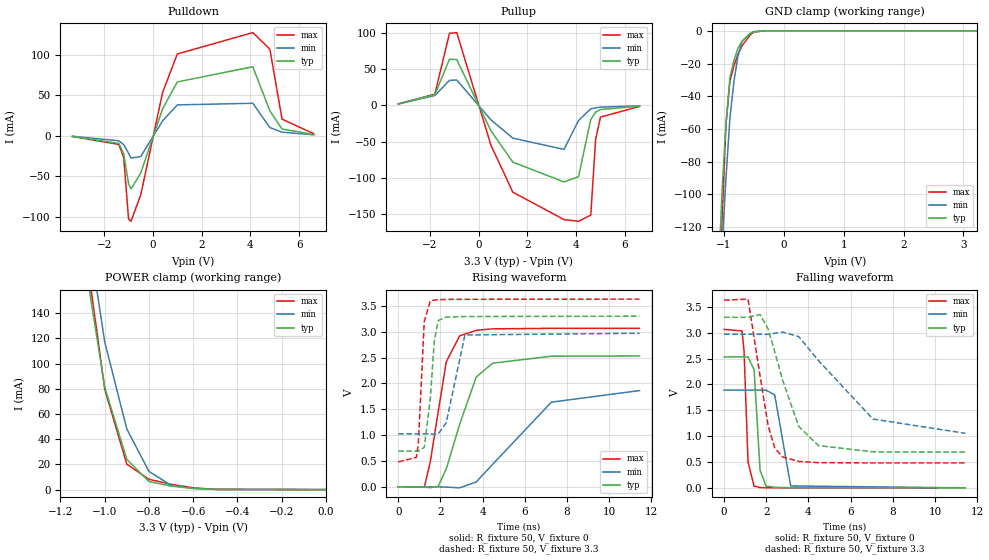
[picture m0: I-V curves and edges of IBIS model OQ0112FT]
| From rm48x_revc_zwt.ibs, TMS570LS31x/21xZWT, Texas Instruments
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|   Model Cell OQ0112FT
|OQ0112FT
[Model]   OQ0112FT
Model_type   3-state
Polarity   Non-Inverting
Enable   Active-Low
Cref =  15.0001pF
Rref =  101.0000M
Vref =  0V
Vmeas =  1.65
C_comp   1.2p   1.2p   1.2p
[Temperature Range]   25   155   -40
[Voltage Range]   3.3   2.97   3.63
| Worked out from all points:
|   slope of the pulldown table from 0 to 0.495 V, typ, clamps not added: 12.4 ohm
|   slope of the pullup table from 0 to 0.495 V, typ, clamps not added: 14.3 ohm
|   GND clamp passes 1 mA (typ) near -0.53 V on its own axis
|   POWER clamp passes 1 mA (typ) near -0.60 V on its own axis
|   rising waveform, R_fixture 50, V_fixture 0: 20-80 % time 1.16ns typ, 2.3ns min, 723ps max; typ from 0 V to 2.53 V
|   rising waveform, R_fixture 50, V_fixture 3.3: 20-80 % time 273ps typ, 435ps min, 217ps max; typ from 0.691 V to 3.3 V
|   falling waveform, R_fixture 50, V_fixture 0: 20-80 % time 215ps typ, 299ps min, 162ps max; typ from 2.53 V to 0 V
|   falling waveform, R_fixture 50, V_fixture 3.3: 20-80 % time 1.21ns typ, 2.37ns min, 728ps max; typ from 3.3 V to 0.69 V
[POWER_clamp]
|   voltage   I(typ)   I(min)   I(max)
-3.3V     4.209A     4.356A     6.25A
-1.067V   155.6mA    193.8mA    165.5mA
-1.033V   118.4mA    155.6mA    122.7mA
-1V       81.27mA    117.3mA    79.78mA
-900mV    24.07mA    48.16mA    20.23mA
-800mV    6.413mA    14.5mA     8.147mA
-700mV    2.797mA    3.392mA    4.243mA
-600mV    930.7uA    981.4uA    1.442mA
-500mV    137uA      226.8uA    190.9uA
0V        418pA      5.717nA    395.4pA
[Pulldown]
|   voltage   I(typ)   I(min)   I(max)
-3.3V     -637.7uA   -591.6uA   -857uA
-1.4V     -9.513mA   -6.163mA   -10.7mA
-1.2V     -22.13mA   -10.97mA   -26.49mA
-1V       -59.17mA   -21.39mA   -102.7mA
-900mV    -65.74mA   -27.54mA   -105.6mA
-500mV    -45.97mA   -25.61mA   -73.03mA
400mV     33.51mA    18.52mA    53.74mA
1V        66.49mA    38.18mA    101mA
4.1V      85.32mA    40.16mA    127.5mA
4.8V      30.81mA    10.21mA    107mA
5.3V      8.374mA    4.458mA    20.52mA
6.6V      1.585mA    1.222mA    2.673mA
[Pullup]
|   voltage   I(typ)   I(min)   I(max)
-3.3V     1.891mA    2.125mA    2.181mA
-1.8V     14.91mA    13.67mA    15.49mA
-1.2V     63.68mA    34.5mA     99.42mA
-900mV    63.26mA    35.08mA    100.5mA
500mV     -34.83mA   -19.84mA   -54.63mA
1.4V      -78.18mA   -45.1mA    -119.6mA
3.5V      -105.5mA   -60.64mA   -157.4mA
4.1V      -98.1mA    -20.7mA    -159.8mA
4.6V      -19.27mA   -4.706mA   -151.2mA
4.8V      -9.272mA   -3.252mA   -46.75mA
5V        -5.655mA   -2.385mA   -16.07mA
6.6V      -779.8uA   -576.2uA   -1.437mA
[GND_clamp]
|   voltage   I(typ)   I(min)   I(max)
-3.3V     -2.62A     -2.031A    -5.347A
-1.1V     -155.6mA   -180.5mA   -208.4mA
-1.033V   -98.93mA   -133mA     -116.8mA
-966.7mV  -56.54mA   -90.41mA   -57.57mA
-900mV    -28.43mA   -52.86mA   -30.6mA
-833.3mV  -18.07mA   -30.97mA   -21.46mA
-766.7mV  -10.69mA   -15.58mA   -14.35mA
-700mV    -6.288mA   -6.711mA   -9.26mA
-566.7mV  -1.75mA    -1.702mA   -2.672mA
-500mV    -450uA     -556.6uA   -674uA
-300mV    -585.6nA   -4.438uA   -465.5nA
3.233V    388.1pA    2.778uA    312.2pA
[Ramp]
| variable   typ   min   max
dV/dt_f   1.603319/1.228195n   1.193757/2.480067n   1.934434/0.7401439n
dV/dt_r   1.538612/1.176961n   1.14683/2.379442n   1.862745/0.7277276n
R_load = 50
[Rising Waveform]
R_fixture = 50
V_fixture = 0
V_fixture_min = 0
V_fixture_max = 0
|   time   V(typ)   V(min)   V(max)
0s        -64.99nV   211.1nV    240.3nV
1.232ns   -5.534mV   -3.644uV   -8.39mV
1.516ns   -15.96mV   155.2uV    476.1mV
1.896ns   10.24mV    -999.7uV   1.459V
2.276ns   347.8mV    -5.953mV   2.418V
2.908ns   1.207V     -20.37mV   2.919V
3.696ns   2.123V     93.54mV    3.027V
4.476ns   2.391V     435mV      3.055V
7.26ns    2.526V     1.637V     3.065V
11.44ns   2.531V     1.861V     3.065V
[Rising Waveform]
R_fixture = 50
V_fixture = 3.3
V_fixture_min = 2.97
V_fixture_max = 3.63
|   time   V(typ)   V(min)   V(max)
0s        690.7mV    1.025V     482.1mV
852ps     689.4mV    1.025V     568.7mV
948ps     686.4mV    1.025V     810.1mV
1.232ns   765.1mV    1.025V     3.195V
1.516ns   1.695V     1.024V     3.595V
1.708ns   2.824V     1.018V     3.611V
1.896ns   3.217V     1.023V     3.619V
2.276ns   3.282V     1.243V     3.624V
3.16ns    3.294V     2.937V     3.627V
11.44ns   3.3V       2.97V      3.63V
[Falling Waveform]
R_fixture = 50
V_fixture = 0
V_fixture_min = 0
V_fixture_max = 0
|   time   V(typ)   V(min)   V(max)
0s        2.531V     1.89V      3.065V
852ps     2.531V     1.89V      3.035V
948ps     2.531V     1.89V      2.643V
1.136ns   2.532V     1.89V      503mV
1.424ns   2.284V     1.89V      34.5mV
1.708ns   342.2mV    1.89V      5.749mV
1.992ns   33.97mV    1.89V      2.62mV
2.404ns   10.85mV    1.796V     1.556mV
3.16ns    2.287mV    37.19mV    589.5uV
11.44ns   9.752uV    143.6uV    6.353uV
[Falling Waveform]
R_fixture = 50
V_fixture = 3.3
V_fixture_min = 2.97
V_fixture_max = 3.63
|   time   V(typ)   V(min)   V(max)
0s        3.3V       2.97V      3.63V
1.136ns   3.299V     2.97V      3.65V
1.708ns   3.352V     2.97V      2.162V
2.088ns   3.075V     2.969V     1.205V
2.404ns   2.631V     2.99V      769.7mV
2.78ns    2.077V     3.012V     597.7mV
3.54ns    1.189V     2.926V     510.9mV
4.476ns   817.7mV    2.462V     488mV
7.06ns    697mV      1.331V     482mV
11.44ns   690.4mV    1.055V     482.1mV
